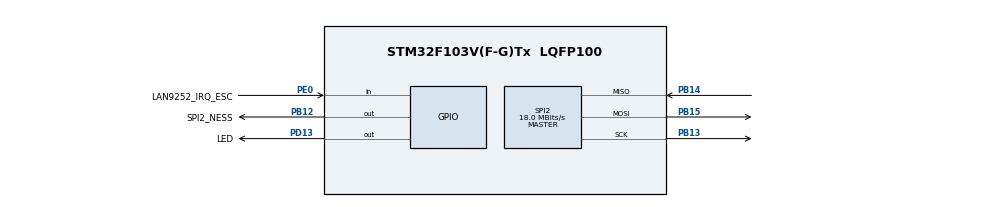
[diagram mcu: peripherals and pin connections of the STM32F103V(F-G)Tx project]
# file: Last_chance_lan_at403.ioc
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Dma.Request0=SPI2_RX
Dma.Request1=SPI2_TX
Dma.SPI2_RX.0.Direction=DMA_PERIPH_TO_MEMORY
Dma.SPI2_RX.0.Instance=DMA1_Channel4
Dma.SPI2_RX.0.MemDataAlignment=DMA_MDATAALIGN_BYTE
Dma.SPI2_RX.0.MemInc=DMA_MINC_ENABLE
Dma.SPI2_RX.0.Mode=DMA_NORMAL
Dma.SPI2_RX.0.PeriphDataAlignment=DMA_PDATAALIGN_BYTE
Dma.SPI2_RX.0.PeriphInc=DMA_PINC_DISABLE
Dma.SPI2_RX.0.Priority=DMA_PRIORITY_LOW
Dma.SPI2_TX.1.Direction=DMA_MEMORY_TO_PERIPH
Dma.SPI2_TX.1.Instance=DMA1_Channel5
Dma.SPI2_TX.1.MemDataAlignment=DMA_MDATAALIGN_BYTE
Dma.SPI2_TX.1.MemInc=DMA_MINC_ENABLE
Dma.SPI2_TX.1.Mode=DMA_NORMAL
Dma.SPI2_TX.1.PeriphDataAlignment=DMA_PDATAALIGN_BYTE
Dma.SPI2_TX.1.PeriphInc=DMA_PINC_DISABLE
Dma.SPI2_TX.1.Priority=DMA_PRIORITY_LOW
Mcu.Family=STM32F1
Mcu.Name=STM32F103V(F-G)Tx
Mcu.Package=LQFP100
NVIC.DMA1_Channel4_IRQn=true\:0\:0\:false\:false\:true\:false\:true
NVIC.DMA1_Channel5_IRQn=true\:0\:0\:false\:false\:true\:false\:true
NVIC.PriorityGroup=NVIC_PRIORITYGROUP_4
NVIC.SPI2_IRQn=true\:0\:0\:false\:false\:true\:true\:true
OSC_IN.Mode=HSE-External-Oscillator
OSC_IN.Signal=RCC_OSC_IN
OSC_OUT.Mode=HSE-External-Oscillator
OSC_OUT.Signal=RCC_OSC_OUT
PA13.Mode=Serial_Wire
PA13.Signal=SYS_JTMS-SWDIO
PA14.Mode=Serial_Wire
PA14.Signal=SYS_JTCK-SWCLK
PB12.GPIO_Label=SPI2_NESS
PB12.Signal=GPIO_Output
PB13.Mode=Full_Duplex_Master
PB13.Signal=SPI2_SCK
PB14.Mode=Full_Duplex_Master
PB14.Signal=SPI2_MISO
PB15.Mode=Full_Duplex_Master
PB15.Signal=SPI2_MOSI
PC14-OSC32_IN.Mode=LSE-External-Oscillator
PC14-OSC32_IN.Signal=RCC_OSC32_IN
PC15-OSC32_OUT.Mode=LSE-External-Oscillator
PC15-OSC32_OUT.Signal=RCC_OSC32_OUT
PD13.GPIO_Label=LED
PD13.Signal=GPIO_Output
PE0.GPIO_Label=LAN9252_IRQ_ESC
PE0.GPIO_PuPd=GPIO_PULLUP
PE0.Signal=GPIO_Input
ProjectManager.HeapSize=0x200
ProjectManager.StackSize=0x400
ProjectManager.TargetToolchain=MDK-ARM V5.27
RCC.AHBFreq_Value=72000000
RCC.APB1CLKDivider=RCC_HCLK_DIV2
RCC.APB1Freq_Value=36000000
RCC.APB1TimFreq_Value=72000000
RCC.APB2Freq_Value=72000000
RCC.APB2TimFreq_Value=72000000
RCC.HCLKFreq_Value=72000000
RCC.PLLMUL=RCC_PLL_MUL9
RCC.PLLSourceVirtual=RCC_PLLSOURCE_HSE
RCC.SYSCLKFreq_VALUE=72000000
RCC.SYSCLKSource=RCC_SYSCLKSOURCE_PLLCLK
RCC.USBFreq_Value=72000000
SPI2.BaudRatePrescaler=SPI_BAUDRATEPRESCALER_2
SPI2.CalculateBaudRate=18.0 MBits/s
SPI2.Direction=SPI_DIRECTION_2LINES
SPI2.Mode=SPI_MODE_MASTER
SPI2.VirtualType=VM_MASTER
board=custom

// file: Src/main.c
/* USER CODE BEGIN Header */
/**
  ******************************************************************************
  * @file           : main.c
  * @brief          : Main program body
  ******************************************************************************
  * @attention
  *
  * <h2><center>&copy; Copyright (c) 2021 STMicroelectronics.
  * All rights reserved.</center></h2>
  *
  * This software component is licensed by ST under BSD 3-Clause license,
  * the "License"; You may not use this file except in compliance with the
  * License. You may obtain a copy of the License at:
  *                        opensource.org/licenses/BSD-3-Clause
  *
  ******************************************************************************
  */
/* USER CODE END Header */

#include "main.h"

/* USER CODE BEGIN Includes */
#include "9252_HW.h"
#include "SPIDriver.h"
#include "ecatappl.h"
#include "ecat_def.h"
#include "ecatslv.h"
#include "objdef.h"
#include "applInterface.h"
#include "pic32_mchp_gpio_sample_app.h"
/* USER CODE END Includes */

SPI_HandleTypeDef hspi2;
DMA_HandleTypeDef hdma_spi2_rx;
DMA_HandleTypeDef hdma_spi2_tx;

void SystemClock_Config(void);
static void MX_GPIO_Init(void);
static void MX_DMA_Init(void);
static void MX_SPI2_Init(void);

/* USER CODE BEGIN 0 */
int cnt = 0 ;
/* USER CODE END 0 */

int main(void)
{

  /* MCU Configuration--------------------------------------------------------*/

  /* Reset of all peripherals, Initializes the Flash interface and the Systick. */
  HAL_Init();

  /* Configure the system clock */
  SystemClock_Config();

  /* Initialize all configured peripherals */
  MX_GPIO_Init();
  MX_DMA_Init();
  MX_SPI2_Init();
  /* USER CODE BEGIN 2 */
	HW_Init();
	MainInit();

	APPL_GenerateMapping(&nPdInputSize,&nPdOutputSize);
  bRunApplication = TRUE;
  /* USER CODE END 2 */

  /* Infinite loop */
  while (1)
  {
		 MainLoop();
		cnt ++ ;
		if(cnt > 5000000)
		{
		cnt=0;
		HAL_GPIO_TogglePin(GPIOD,GPIO_PIN_13);
		}
  }
}

void SystemClock_Config(void)
{
  RCC_OscInitTypeDef RCC_OscInitStruct = {0};
  RCC_ClkInitTypeDef RCC_ClkInitStruct = {0};

  /** Initializes the CPU, AHB and APB busses clocks
  */
  RCC_OscInitStruct.OscillatorType = RCC_OSCILLATORTYPE_HSE;
  RCC_OscInitStruct.HSEState = RCC_HSE_ON;
  RCC_OscInitStruct.HSEPredivValue = RCC_HSE_PREDIV_DIV1;
  RCC_OscInitStruct.HSIState = RCC_HSI_ON;
  RCC_OscInitStruct.PLL.PLLState = RCC_PLL_ON;
  RCC_OscInitStruct.PLL.PLLSource = RCC_PLLSOURCE_HSE;
  RCC_OscInitStruct.PLL.PLLMUL = RCC_PLL_MUL16;
  if (HAL_RCC_OscConfig(&RCC_OscInitStruct) != HAL_OK)
  {
    Error_Handler();
  }
  /** Initializes the CPU, AHB and APB busses clocks
  */
  RCC_ClkInitStruct.ClockType = RCC_CLOCKTYPE_HCLK|RCC_CLOCKTYPE_SYSCLK
                              |RCC_CLOCKTYPE_PCLK1|RCC_CLOCKTYPE_PCLK2;
  RCC_ClkInitStruct.SYSCLKSource = RCC_SYSCLKSOURCE_PLLCLK;
  RCC_ClkInitStruct.AHBCLKDivider = RCC_SYSCLK_DIV1;
  RCC_ClkInitStruct.APB1CLKDivider = RCC_HCLK_DIV2;
  RCC_ClkInitStruct.APB2CLKDivider = RCC_HCLK_DIV1;

  if (HAL_RCC_ClockConfig(&RCC_ClkInitStruct, FLASH_LATENCY_2) != HAL_OK)
  {
    Error_Handler();
  }
}

static void MX_SPI2_Init(void)
{

  /* SPI2 parameter configuration*/
  hspi2.Instance = SPI2;
  hspi2.Init.Mode = SPI_MODE_MASTER;
  hspi2.Init.Direction = SPI_DIRECTION_2LINES;
  hspi2.Init.DataSize = SPI_DATASIZE_8BIT;
  hspi2.Init.CLKPolarity = SPI_POLARITY_LOW;
  hspi2.Init.CLKPhase = SPI_PHASE_1EDGE;
  hspi2.Init.NSS = SPI_NSS_SOFT;
  hspi2.Init.BaudRatePrescaler = SPI_BAUDRATEPRESCALER_4;
  hspi2.Init.FirstBit = SPI_FIRSTBIT_MSB;
  hspi2.Init.TIMode = SPI_TIMODE_DISABLE;
  hspi2.Init.CRCCalculation = SPI_CRCCALCULATION_DISABLE;
  hspi2.Init.CRCPolynomial = 10;
  if (HAL_SPI_Init(&hspi2) != HAL_OK)
  {
    Error_Handler();
  }

}

static void MX_DMA_Init(void)
{

  /* DMA controller clock enable */
  __HAL_RCC_DMA1_CLK_ENABLE();

  /* DMA interrupt init */
  /* DMA1_Channel4_IRQn interrupt configuration */
  HAL_NVIC_SetPriority(DMA1_Channel4_IRQn, 0, 0);
  HAL_NVIC_EnableIRQ(DMA1_Channel4_IRQn);
  /* DMA1_Channel5_IRQn interrupt configuration */
  HAL_NVIC_SetPriority(DMA1_Channel5_IRQn, 0, 0);
  HAL_NVIC_EnableIRQ(DMA1_Channel5_IRQn);

}

static void MX_GPIO_Init(void)
{
  GPIO_InitTypeDef GPIO_InitStruct = {0};

  /* GPIO Ports Clock Enable */
  __HAL_RCC_GPIOC_CLK_ENABLE();
  __HAL_RCC_GPIOB_CLK_ENABLE();
  __HAL_RCC_GPIOD_CLK_ENABLE();
  __HAL_RCC_GPIOA_CLK_ENABLE();
  __HAL_RCC_GPIOE_CLK_ENABLE();

  /*Configure GPIO pin Output Level */
  HAL_GPIO_WritePin(SPI2_NESS_GPIO_Port, SPI2_NESS_Pin, GPIO_PIN_RESET);

  /*Configure GPIO pin Output Level */
  HAL_GPIO_WritePin(LED_GPIO_Port, LED_Pin, GPIO_PIN_RESET);

  /*Configure GPIO pin : SPI2_NESS_Pin */
  GPIO_InitStruct.Pin = SPI2_NESS_Pin;
  GPIO_InitStruct.Mode = GPIO_MODE_OUTPUT_PP;
  GPIO_InitStruct.Pull = GPIO_NOPULL;
  GPIO_InitStruct.Speed = GPIO_SPEED_FREQ_LOW;
  HAL_GPIO_Init(SPI2_NESS_GPIO_Port, &GPIO_InitStruct);

  /*Configure GPIO pin : LED_Pin */
  GPIO_InitStruct.Pin = LED_Pin;
  GPIO_InitStruct.Mode = GPIO_MODE_OUTPUT_PP;
  GPIO_InitStruct.Pull = GPIO_NOPULL;
  GPIO_InitStruct.Speed = GPIO_SPEED_FREQ_LOW;
  HAL_GPIO_Init(LED_GPIO_Port, &GPIO_InitStruct);

  /*Configure GPIO pin : LAN9252_IRQ_ESC_Pin */
  GPIO_InitStruct.Pin = LAN9252_IRQ_ESC_Pin;
  GPIO_InitStruct.Mode = GPIO_MODE_INPUT;
  GPIO_InitStruct.Pull = GPIO_PULLUP;
  HAL_GPIO_Init(LAN9252_IRQ_ESC_GPIO_Port, &GPIO_InitStruct);

}

void Error_Handler(void)
{
}

/************************ (C) COPYRIGHT STMicroelectronics *****END OF FILE****/
